# Generated by OpenFakeRAM
VERSION 5.7 ;
BUSBITCHARS "[]" ;
PROPERTYDEFINITIONS
  MACRO width INTEGER ;
  MACRO depth INTEGER ;
  MACRO banks INTEGER ;
END PROPERTYDEFINITIONS
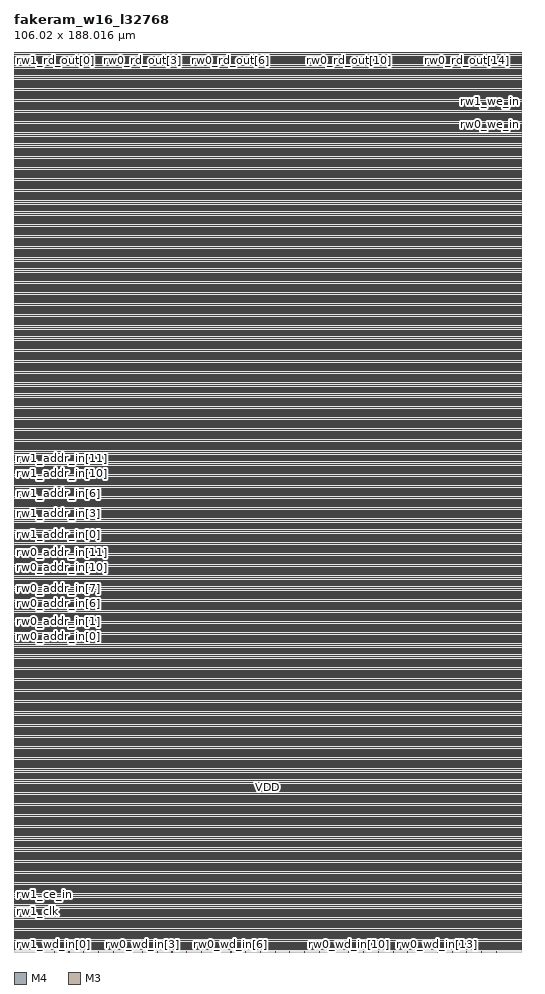
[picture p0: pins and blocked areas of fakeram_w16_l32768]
MACRO fakeram_w16_l32768
  PROPERTY width 16 ;
  PROPERTY depth 16384 ;
  PROPERTY banks 1 ;
  FOREIGN fakeram_w16_l32768 0 0 ;
  SYMMETRY X Y R90 ;
  SIZE 106.020 BY 188.016 ;
  CLASS BLOCK ;
  PIN rw0_clk
    DIRECTION INPUT ;
    USE SIGNAL ;
    SHAPE ABUTMENT ;
    PORT
      LAYER M4 ;
      RECT 0.000 5.652 0.048 5.676 ;
    END
  END rw0_clk
  PIN rw0_ce_in
    DIRECTION INPUT ;
    USE SIGNAL ;
    SHAPE ABUTMENT ;
    PORT
      LAYER M4 ;
      RECT 0.000 7.476 0.048 7.500 ;
    END
  END rw0_ce_in
  PIN rw1_clk
    DIRECTION INPUT ;
    USE SIGNAL ;
    SHAPE ABUTMENT ;
    PORT
      LAYER M4 ;
      RECT 0.000 8.484 0.048 8.508 ;
    END
  END rw1_clk
  PIN rw1_ce_in
    DIRECTION INPUT ;
    USE SIGNAL ;
    SHAPE ABUTMENT ;
    PORT
      LAYER M4 ;
      RECT 0.000 10.308 0.048 10.332 ;
    END
  END rw1_ce_in
  PIN rw0_addr_in[0]
    DIRECTION INPUT ;
    USE SIGNAL ;
    SHAPE ABUTMENT ;
    PORT
      LAYER M4 ;
      RECT 0.000 65.844 0.048 65.868 ;
    END
  END rw0_addr_in[0]
  PIN rw0_addr_in[1]
    DIRECTION INPUT ;
    USE SIGNAL ;
    SHAPE ABUTMENT ;
    PORT
      LAYER M4 ;
      RECT 0.000 67.284 0.048 67.308 ;
    END
  END rw0_addr_in[1]
  PIN rw0_addr_in[2]
    DIRECTION INPUT ;
    USE SIGNAL ;
    SHAPE ABUTMENT ;
    PORT
      LAYER M4 ;
      RECT 0.000 68.724 0.048 68.748 ;
    END
  END rw0_addr_in[2]
  PIN rw0_addr_in[3]
    DIRECTION INPUT ;
    USE SIGNAL ;
    SHAPE ABUTMENT ;
    PORT
      LAYER M4 ;
      RECT 0.000 70.164 0.048 70.188 ;
    END
  END rw0_addr_in[3]
  PIN rw0_addr_in[4]
    DIRECTION INPUT ;
    USE SIGNAL ;
    SHAPE ABUTMENT ;
    PORT
      LAYER M4 ;
      RECT 0.000 71.604 0.048 71.628 ;
    END
  END rw0_addr_in[4]
  PIN rw0_addr_in[5]
    DIRECTION INPUT ;
    USE SIGNAL ;
    SHAPE ABUTMENT ;
    PORT
      LAYER M4 ;
      RECT 0.000 73.044 0.048 73.068 ;
    END
  END rw0_addr_in[5]
  PIN rw0_addr_in[6]
    DIRECTION INPUT ;
    USE SIGNAL ;
    SHAPE ABUTMENT ;
    PORT
      LAYER M4 ;
      RECT 0.000 74.484 0.048 74.508 ;
    END
  END rw0_addr_in[6]
  PIN rw0_addr_in[7]
    DIRECTION INPUT ;
    USE SIGNAL ;
    SHAPE ABUTMENT ;
    PORT
      LAYER M4 ;
      RECT 0.000 75.924 0.048 75.948 ;
    END
  END rw0_addr_in[7]
  PIN rw0_addr_in[8]
    DIRECTION INPUT ;
    USE SIGNAL ;
    SHAPE ABUTMENT ;
    PORT
      LAYER M4 ;
      RECT 0.000 77.364 0.048 77.388 ;
    END
  END rw0_addr_in[8]
  PIN rw0_addr_in[9]
    DIRECTION INPUT ;
    USE SIGNAL ;
    SHAPE ABUTMENT ;
    PORT
      LAYER M4 ;
      RECT 0.000 78.804 0.048 78.828 ;
    END
  END rw0_addr_in[9]
  PIN rw0_addr_in[10]
    DIRECTION INPUT ;
    USE SIGNAL ;
    SHAPE ABUTMENT ;
    PORT
      LAYER M4 ;
      RECT 0.000 80.244 0.048 80.268 ;
    END
  END rw0_addr_in[10]
  PIN rw0_addr_in[11]
    DIRECTION INPUT ;
    USE SIGNAL ;
    SHAPE ABUTMENT ;
    PORT
      LAYER M4 ;
      RECT 0.000 81.684 0.048 81.708 ;
    END
  END rw0_addr_in[11]
  PIN rw0_addr_in[12]
    DIRECTION INPUT ;
    USE SIGNAL ;
    SHAPE ABUTMENT ;
    PORT
      LAYER M4 ;
      RECT 0.000 83.124 0.048 83.148 ;
    END
  END rw0_addr_in[12]
  PIN rw0_addr_in[13]
    DIRECTION INPUT ;
    USE SIGNAL ;
    SHAPE ABUTMENT ;
    PORT
      LAYER M4 ;
      RECT 0.000 84.564 0.048 84.588 ;
    END
  END rw0_addr_in[13]
  PIN rw1_addr_in[0]
    DIRECTION INPUT ;
    USE SIGNAL ;
    SHAPE ABUTMENT ;
    PORT
      LAYER M4 ;
      RECT 0.000 85.572 0.048 85.596 ;
    END
  END rw1_addr_in[0]
  PIN rw1_addr_in[1]
    DIRECTION INPUT ;
    USE SIGNAL ;
    SHAPE ABUTMENT ;
    PORT
      LAYER M4 ;
      RECT 0.000 87.012 0.048 87.036 ;
    END
  END rw1_addr_in[1]
  PIN rw1_addr_in[2]
    DIRECTION INPUT ;
    USE SIGNAL ;
    SHAPE ABUTMENT ;
    PORT
      LAYER M4 ;
      RECT 0.000 88.452 0.048 88.476 ;
    END
  END rw1_addr_in[2]
  PIN rw1_addr_in[3]
    DIRECTION INPUT ;
    USE SIGNAL ;
    SHAPE ABUTMENT ;
    PORT
      LAYER M4 ;
      RECT 0.000 89.892 0.048 89.916 ;
    END
  END rw1_addr_in[3]
  PIN rw1_addr_in[4]
    DIRECTION INPUT ;
    USE SIGNAL ;
    SHAPE ABUTMENT ;
    PORT
      LAYER M4 ;
      RECT 0.000 91.332 0.048 91.356 ;
    END
  END rw1_addr_in[4]
  PIN rw1_addr_in[5]
    DIRECTION INPUT ;
    USE SIGNAL ;
    SHAPE ABUTMENT ;
    PORT
      LAYER M4 ;
      RECT 0.000 92.772 0.048 92.796 ;
    END
  END rw1_addr_in[5]
  PIN rw1_addr_in[6]
    DIRECTION INPUT ;
    USE SIGNAL ;
    SHAPE ABUTMENT ;
    PORT
      LAYER M4 ;
      RECT 0.000 94.212 0.048 94.236 ;
    END
  END rw1_addr_in[6]
  PIN rw1_addr_in[7]
    DIRECTION INPUT ;
    USE SIGNAL ;
    SHAPE ABUTMENT ;
    PORT
      LAYER M4 ;
      RECT 0.000 95.700 0.048 95.724 ;
    END
  END rw1_addr_in[7]
  PIN rw1_addr_in[8]
    DIRECTION INPUT ;
    USE SIGNAL ;
    SHAPE ABUTMENT ;
    PORT
      LAYER M4 ;
      RECT 0.000 97.140 0.048 97.164 ;
    END
  END rw1_addr_in[8]
  PIN rw1_addr_in[9]
    DIRECTION INPUT ;
    USE SIGNAL ;
    SHAPE ABUTMENT ;
    PORT
      LAYER M4 ;
      RECT 0.000 98.580 0.048 98.604 ;
    END
  END rw1_addr_in[9]
  PIN rw1_addr_in[10]
    DIRECTION INPUT ;
    USE SIGNAL ;
    SHAPE ABUTMENT ;
    PORT
      LAYER M4 ;
      RECT 0.000 100.020 0.048 100.044 ;
    END
  END rw1_addr_in[10]
  PIN rw1_addr_in[11]
    DIRECTION INPUT ;
    USE SIGNAL ;
    SHAPE ABUTMENT ;
    PORT
      LAYER M4 ;
      RECT 0.000 101.460 0.048 101.484 ;
    END
  END rw1_addr_in[11]
  PIN rw1_addr_in[12]
    DIRECTION INPUT ;
    USE SIGNAL ;
    SHAPE ABUTMENT ;
    PORT
      LAYER M4 ;
      RECT 0.000 102.900 0.048 102.924 ;
    END
  END rw1_addr_in[12]
  PIN rw1_addr_in[13]
    DIRECTION INPUT ;
    USE SIGNAL ;
    SHAPE ABUTMENT ;
    PORT
      LAYER M4 ;
      RECT 0.000 104.340 0.048 104.364 ;
    END
  END rw1_addr_in[13]
  PIN rw1_rd_out[0]
    DIRECTION OUTPUT ;
    USE SIGNAL ;
    SHAPE ABUTMENT ;
    PORT
      LAYER M3 ;
      RECT 5.319 187.980 5.337 188.016 ;
    END
  END rw1_rd_out[0]
  PIN rw0_rd_out[0]
    DIRECTION OUTPUT ;
    USE SIGNAL ;
    SHAPE ABUTMENT ;
    PORT
      LAYER M3 ;
      RECT 8.379 187.980 8.397 188.016 ;
    END
  END rw0_rd_out[0]
  PIN rw1_rd_out[1]
    DIRECTION OUTPUT ;
    USE SIGNAL ;
    SHAPE ABUTMENT ;
    PORT
      LAYER M3 ;
      RECT 11.475 187.980 11.493 188.016 ;
    END
  END rw1_rd_out[1]
  PIN rw0_rd_out[1]
    DIRECTION OUTPUT ;
    USE SIGNAL ;
    SHAPE ABUTMENT ;
    PORT
      LAYER M3 ;
      RECT 14.535 187.980 14.553 188.016 ;
    END
  END rw0_rd_out[1]
  PIN rw1_rd_out[2]
    DIRECTION OUTPUT ;
    USE SIGNAL ;
    SHAPE ABUTMENT ;
    PORT
      LAYER M3 ;
      RECT 17.631 187.980 17.649 188.016 ;
    END
  END rw1_rd_out[2]
  PIN rw0_rd_out[2]
    DIRECTION OUTPUT ;
    USE SIGNAL ;
    SHAPE ABUTMENT ;
    PORT
      LAYER M3 ;
      RECT 20.691 187.980 20.709 188.016 ;
    END
  END rw0_rd_out[2]
  PIN rw1_rd_out[3]
    DIRECTION OUTPUT ;
    USE SIGNAL ;
    SHAPE ABUTMENT ;
    PORT
      LAYER M3 ;
      RECT 23.787 187.980 23.805 188.016 ;
    END
  END rw1_rd_out[3]
  PIN rw0_rd_out[3]
    DIRECTION OUTPUT ;
    USE SIGNAL ;
    SHAPE ABUTMENT ;
    PORT
      LAYER M3 ;
      RECT 26.847 187.980 26.865 188.016 ;
    END
  END rw0_rd_out[3]
  PIN rw1_rd_out[4]
    DIRECTION OUTPUT ;
    USE SIGNAL ;
    SHAPE ABUTMENT ;
    PORT
      LAYER M3 ;
      RECT 29.943 187.980 29.961 188.016 ;
    END
  END rw1_rd_out[4]
  PIN rw0_rd_out[4]
    DIRECTION OUTPUT ;
    USE SIGNAL ;
    SHAPE ABUTMENT ;
    PORT
      LAYER M3 ;
      RECT 33.003 187.980 33.021 188.016 ;
    END
  END rw0_rd_out[4]
  PIN rw1_rd_out[5]
    DIRECTION OUTPUT ;
    USE SIGNAL ;
    SHAPE ABUTMENT ;
    PORT
      LAYER M3 ;
      RECT 36.099 187.980 36.117 188.016 ;
    END
  END rw1_rd_out[5]
  PIN rw0_rd_out[5]
    DIRECTION OUTPUT ;
    USE SIGNAL ;
    SHAPE ABUTMENT ;
    PORT
      LAYER M3 ;
      RECT 39.159 187.980 39.177 188.016 ;
    END
  END rw0_rd_out[5]
  PIN rw1_rd_out[6]
    DIRECTION OUTPUT ;
    USE SIGNAL ;
    SHAPE ABUTMENT ;
    PORT
      LAYER M3 ;
      RECT 42.255 187.980 42.273 188.016 ;
    END
  END rw1_rd_out[6]
  PIN rw0_rd_out[6]
    DIRECTION OUTPUT ;
    USE SIGNAL ;
    SHAPE ABUTMENT ;
    PORT
      LAYER M3 ;
      RECT 45.315 187.980 45.333 188.016 ;
    END
  END rw0_rd_out[6]
  PIN rw1_rd_out[7]
    DIRECTION OUTPUT ;
    USE SIGNAL ;
    SHAPE ABUTMENT ;
    PORT
      LAYER M3 ;
      RECT 48.411 187.980 48.429 188.016 ;
    END
  END rw1_rd_out[7]
  PIN rw0_rd_out[7]
    DIRECTION OUTPUT ;
    USE SIGNAL ;
    SHAPE ABUTMENT ;
    PORT
      LAYER M3 ;
      RECT 51.471 187.980 51.489 188.016 ;
    END
  END rw0_rd_out[7]
  PIN rw1_rd_out[8]
    DIRECTION OUTPUT ;
    USE SIGNAL ;
    SHAPE ABUTMENT ;
    PORT
      LAYER M3 ;
      RECT 54.567 187.980 54.585 188.016 ;
    END
  END rw1_rd_out[8]
  PIN rw0_rd_out[8]
    DIRECTION OUTPUT ;
    USE SIGNAL ;
    SHAPE ABUTMENT ;
    PORT
      LAYER M3 ;
      RECT 57.627 187.980 57.645 188.016 ;
    END
  END rw0_rd_out[8]
  PIN rw1_rd_out[9]
    DIRECTION OUTPUT ;
    USE SIGNAL ;
    SHAPE ABUTMENT ;
    PORT
      LAYER M3 ;
      RECT 60.723 187.980 60.741 188.016 ;
    END
  END rw1_rd_out[9]
  PIN rw0_rd_out[9]
    DIRECTION OUTPUT ;
    USE SIGNAL ;
    SHAPE ABUTMENT ;
    PORT
      LAYER M3 ;
      RECT 63.783 187.980 63.801 188.016 ;
    END
  END rw0_rd_out[9]
  PIN rw1_rd_out[10]
    DIRECTION OUTPUT ;
    USE SIGNAL ;
    SHAPE ABUTMENT ;
    PORT
      LAYER M3 ;
      RECT 66.879 187.980 66.897 188.016 ;
    END
  END rw1_rd_out[10]
  PIN rw0_rd_out[10]
    DIRECTION OUTPUT ;
    USE SIGNAL ;
    SHAPE ABUTMENT ;
    PORT
      LAYER M3 ;
      RECT 69.939 187.980 69.957 188.016 ;
    END
  END rw0_rd_out[10]
  PIN rw1_rd_out[11]
    DIRECTION OUTPUT ;
    USE SIGNAL ;
    SHAPE ABUTMENT ;
    PORT
      LAYER M3 ;
      RECT 73.035 187.980 73.053 188.016 ;
    END
  END rw1_rd_out[11]
  PIN rw0_rd_out[11]
    DIRECTION OUTPUT ;
    USE SIGNAL ;
    SHAPE ABUTMENT ;
    PORT
      LAYER M3 ;
      RECT 76.095 187.980 76.113 188.016 ;
    END
  END rw0_rd_out[11]
  PIN rw1_rd_out[12]
    DIRECTION OUTPUT ;
    USE SIGNAL ;
    SHAPE ABUTMENT ;
    PORT
      LAYER M3 ;
      RECT 79.191 187.980 79.209 188.016 ;
    END
  END rw1_rd_out[12]
  PIN rw0_rd_out[12]
    DIRECTION OUTPUT ;
    USE SIGNAL ;
    SHAPE ABUTMENT ;
    PORT
      LAYER M3 ;
      RECT 82.251 187.980 82.269 188.016 ;
    END
  END rw0_rd_out[12]
  PIN rw1_rd_out[13]
    DIRECTION OUTPUT ;
    USE SIGNAL ;
    SHAPE ABUTMENT ;
    PORT
      LAYER M3 ;
      RECT 85.347 187.980 85.365 188.016 ;
    END
  END rw1_rd_out[13]
  PIN rw0_rd_out[13]
    DIRECTION OUTPUT ;
    USE SIGNAL ;
    SHAPE ABUTMENT ;
    PORT
      LAYER M3 ;
      RECT 88.407 187.980 88.425 188.016 ;
    END
  END rw0_rd_out[13]
  PIN rw1_rd_out[14]
    DIRECTION OUTPUT ;
    USE SIGNAL ;
    SHAPE ABUTMENT ;
    PORT
      LAYER M3 ;
      RECT 91.503 187.980 91.521 188.016 ;
    END
  END rw1_rd_out[14]
  PIN rw0_rd_out[14]
    DIRECTION OUTPUT ;
    USE SIGNAL ;
    SHAPE ABUTMENT ;
    PORT
      LAYER M3 ;
      RECT 94.563 187.980 94.581 188.016 ;
    END
  END rw0_rd_out[14]
  PIN rw1_rd_out[15]
    DIRECTION OUTPUT ;
    USE SIGNAL ;
    SHAPE ABUTMENT ;
    PORT
      LAYER M3 ;
      RECT 97.659 187.980 97.677 188.016 ;
    END
  END rw1_rd_out[15]
  PIN rw0_rd_out[15]
    DIRECTION OUTPUT ;
    USE SIGNAL ;
    SHAPE ABUTMENT ;
    PORT
      LAYER M3 ;
      RECT 100.719 187.980 100.737 188.016 ;
    END
  END rw0_rd_out[15]
  PIN rw0_we_in
    DIRECTION INPUT ;
    USE SIGNAL ;
    SHAPE ABUTMENT ;
    PORT
      LAYER M4 ;
      RECT 105.972 172.932 106.020 172.956 ;
    END
  END rw0_we_in
  PIN rw1_we_in
    DIRECTION INPUT ;
    USE SIGNAL ;
    SHAPE ABUTMENT ;
    PORT
      LAYER M4 ;
      RECT 105.972 177.636 106.020 177.660 ;
    END
  END rw1_we_in
  PIN rw1_wd_in[0]
    DIRECTION INPUT ;
    USE SIGNAL ;
    SHAPE ABUTMENT ;
    PORT
      LAYER M3 ;
      RECT 5.319 0.000 5.337 0.036 ;
    END
  END rw1_wd_in[0]
  PIN rw0_wd_in[0]
    DIRECTION INPUT ;
    USE SIGNAL ;
    SHAPE ABUTMENT ;
    PORT
      LAYER M3 ;
      RECT 8.379 0.000 8.397 0.036 ;
    END
  END rw0_wd_in[0]
  PIN rw1_wd_in[1]
    DIRECTION INPUT ;
    USE SIGNAL ;
    SHAPE ABUTMENT ;
    PORT
      LAYER M3 ;
      RECT 11.475 0.000 11.493 0.036 ;
    END
  END rw1_wd_in[1]
  PIN rw0_wd_in[1]
    DIRECTION INPUT ;
    USE SIGNAL ;
    SHAPE ABUTMENT ;
    PORT
      LAYER M3 ;
      RECT 14.535 0.000 14.553 0.036 ;
    END
  END rw0_wd_in[1]
  PIN rw1_wd_in[2]
    DIRECTION INPUT ;
    USE SIGNAL ;
    SHAPE ABUTMENT ;
    PORT
      LAYER M3 ;
      RECT 17.631 0.000 17.649 0.036 ;
    END
  END rw1_wd_in[2]
  PIN rw0_wd_in[2]
    DIRECTION INPUT ;
    USE SIGNAL ;
    SHAPE ABUTMENT ;
    PORT
      LAYER M3 ;
      RECT 20.691 0.000 20.709 0.036 ;
    END
  END rw0_wd_in[2]
  PIN rw1_wd_in[3]
    DIRECTION INPUT ;
    USE SIGNAL ;
    SHAPE ABUTMENT ;
    PORT
      LAYER M3 ;
      RECT 23.787 0.000 23.805 0.036 ;
    END
  END rw1_wd_in[3]
  PIN rw0_wd_in[3]
    DIRECTION INPUT ;
    USE SIGNAL ;
    SHAPE ABUTMENT ;
    PORT
      LAYER M3 ;
      RECT 26.847 0.000 26.865 0.036 ;
    END
  END rw0_wd_in[3]
  PIN rw1_wd_in[4]
    DIRECTION INPUT ;
    USE SIGNAL ;
    SHAPE ABUTMENT ;
    PORT
      LAYER M3 ;
      RECT 29.943 0.000 29.961 0.036 ;
    END
  END rw1_wd_in[4]
  PIN rw0_wd_in[4]
    DIRECTION INPUT ;
    USE SIGNAL ;
    SHAPE ABUTMENT ;
    PORT
      LAYER M3 ;
      RECT 33.003 0.000 33.021 0.036 ;
    END
  END rw0_wd_in[4]
  PIN rw1_wd_in[5]
    DIRECTION INPUT ;
    USE SIGNAL ;
    SHAPE ABUTMENT ;
    PORT
      LAYER M3 ;
      RECT 36.099 0.000 36.117 0.036 ;
    END
  END rw1_wd_in[5]
  PIN rw0_wd_in[5]
    DIRECTION INPUT ;
    USE SIGNAL ;
    SHAPE ABUTMENT ;
    PORT
      LAYER M3 ;
      RECT 39.159 0.000 39.177 0.036 ;
    END
  END rw0_wd_in[5]
  PIN rw1_wd_in[6]
    DIRECTION INPUT ;
    USE SIGNAL ;
    SHAPE ABUTMENT ;
    PORT
      LAYER M3 ;
      RECT 42.255 0.000 42.273 0.036 ;
    END
  END rw1_wd_in[6]
  PIN rw0_wd_in[6]
    DIRECTION INPUT ;
    USE SIGNAL ;
    SHAPE ABUTMENT ;
    PORT
      LAYER M3 ;
      RECT 45.315 0.000 45.333 0.036 ;
    END
  END rw0_wd_in[6]
  PIN rw1_wd_in[7]
    DIRECTION INPUT ;
    USE SIGNAL ;
    SHAPE ABUTMENT ;
    PORT
      LAYER M3 ;
      RECT 48.411 0.000 48.429 0.036 ;
    END
  END rw1_wd_in[7]
  PIN rw0_wd_in[7]
    DIRECTION INPUT ;
    USE SIGNAL ;
    SHAPE ABUTMENT ;
    PORT
      LAYER M3 ;
      RECT 51.471 0.000 51.489 0.036 ;
    END
  END rw0_wd_in[7]
  PIN rw1_wd_in[8]
    DIRECTION INPUT ;
    USE SIGNAL ;
    SHAPE ABUTMENT ;
    PORT
      LAYER M3 ;
      RECT 54.567 0.000 54.585 0.036 ;
    END
  END rw1_wd_in[8]
  PIN rw0_wd_in[8]
    DIRECTION INPUT ;
    USE SIGNAL ;
    SHAPE ABUTMENT ;
    PORT
      LAYER M3 ;
      RECT 57.627 0.000 57.645 0.036 ;
    END
  END rw0_wd_in[8]
  PIN rw1_wd_in[9]
    DIRECTION INPUT ;
    USE SIGNAL ;
    SHAPE ABUTMENT ;
    PORT
      LAYER M3 ;
      RECT 60.723 0.000 60.741 0.036 ;
    END
  END rw1_wd_in[9]
  PIN rw0_wd_in[9]
    DIRECTION INPUT ;
    USE SIGNAL ;
    SHAPE ABUTMENT ;
    PORT
      LAYER M3 ;
      RECT 63.783 0.000 63.801 0.036 ;
    END
  END rw0_wd_in[9]
  PIN rw1_wd_in[10]
    DIRECTION INPUT ;
    USE SIGNAL ;
    SHAPE ABUTMENT ;
    PORT
      LAYER M3 ;
      RECT 66.879 0.000 66.897 0.036 ;
    END
  END rw1_wd_in[10]
  PIN rw0_wd_in[10]
    DIRECTION INPUT ;
    USE SIGNAL ;
    SHAPE ABUTMENT ;
    PORT
      LAYER M3 ;
      RECT 69.939 0.000 69.957 0.036 ;
    END
  END rw0_wd_in[10]
  PIN rw1_wd_in[11]
    DIRECTION INPUT ;
    USE SIGNAL ;
    SHAPE ABUTMENT ;
    PORT
      LAYER M3 ;
      RECT 73.035 0.000 73.053 0.036 ;
    END
  END rw1_wd_in[11]
  PIN rw0_wd_in[11]
    DIRECTION INPUT ;
    USE SIGNAL ;
    SHAPE ABUTMENT ;
    PORT
      LAYER M3 ;
      RECT 76.095 0.000 76.113 0.036 ;
    END
  END rw0_wd_in[11]
  PIN rw1_wd_in[12]
    DIRECTION INPUT ;
    USE SIGNAL ;
    SHAPE ABUTMENT ;
    PORT
      LAYER M3 ;
      RECT 79.191 0.000 79.209 0.036 ;
    END
  END rw1_wd_in[12]
  PIN rw0_wd_in[12]
    DIRECTION INPUT ;
    USE SIGNAL ;
    SHAPE ABUTMENT ;
    PORT
      LAYER M3 ;
      RECT 82.251 0.000 82.269 0.036 ;
    END
  END rw0_wd_in[12]
  PIN rw1_wd_in[13]
    DIRECTION INPUT ;
    USE SIGNAL ;
    SHAPE ABUTMENT ;
    PORT
      LAYER M3 ;
      RECT 85.347 0.000 85.365 0.036 ;
    END
  END rw1_wd_in[13]
  PIN rw0_wd_in[13]
    DIRECTION INPUT ;
    USE SIGNAL ;
    SHAPE ABUTMENT ;
    PORT
      LAYER M3 ;
      RECT 88.407 0.000 88.425 0.036 ;
    END
  END rw0_wd_in[13]
  PIN rw1_wd_in[14]
    DIRECTION INPUT ;
    USE SIGNAL ;
    SHAPE ABUTMENT ;
    PORT
      LAYER M3 ;
      RECT 91.503 0.000 91.521 0.036 ;
    END
  END rw1_wd_in[14]
  PIN rw0_wd_in[14]
    DIRECTION INPUT ;
    USE SIGNAL ;
    SHAPE ABUTMENT ;
    PORT
      LAYER M3 ;
      RECT 94.563 0.000 94.581 0.036 ;
    END
  END rw0_wd_in[14]
  PIN rw1_wd_in[15]
    DIRECTION INPUT ;
    USE SIGNAL ;
    SHAPE ABUTMENT ;
    PORT
      LAYER M3 ;
      RECT 97.659 0.000 97.677 0.036 ;
    END
  END rw1_wd_in[15]
  PIN rw0_wd_in[15]
    DIRECTION INPUT ;
    USE SIGNAL ;
    SHAPE ABUTMENT ;
    PORT
      LAYER M3 ;
      RECT 100.719 0.000 100.737 0.036 ;
    END
  END rw0_wd_in[15]
  PIN VSS
    DIRECTION INOUT ;
    USE GROUND ;
    PORT
      LAYER M4 ;
      RECT 0.096 0.816 105.924 0.912 ;
      RECT 0.096 1.584 105.924 1.680 ;
      RECT 0.096 2.352 105.924 2.448 ;
      RECT 0.096 3.120 105.924 3.216 ;
      RECT 0.096 3.888 105.924 3.984 ;
      RECT 0.096 4.656 105.924 4.752 ;
      RECT 0.096 5.424 105.924 5.520 ;
      RECT 0.096 6.192 105.924 6.288 ;
      RECT 0.096 6.960 105.924 7.056 ;
      RECT 0.096 7.728 105.924 7.824 ;
      RECT 0.096 8.496 105.924 8.592 ;
      RECT 0.096 9.264 105.924 9.360 ;
      RECT 0.096 10.032 105.924 10.128 ;
      RECT 0.096 10.800 105.924 10.896 ;
      RECT 0.096 11.568 105.924 11.664 ;
      RECT 0.096 12.336 105.924 12.432 ;
      RECT 0.096 13.104 105.924 13.200 ;
      RECT 0.096 13.872 105.924 13.968 ;
      RECT 0.096 14.640 105.924 14.736 ;
      RECT 0.096 15.408 105.924 15.504 ;
      RECT 0.096 16.176 105.924 16.272 ;
      RECT 0.096 16.944 105.924 17.040 ;
      RECT 0.096 17.712 105.924 17.808 ;
      RECT 0.096 18.480 105.924 18.576 ;
      RECT 0.096 19.248 105.924 19.344 ;
      RECT 0.096 20.016 105.924 20.112 ;
      RECT 0.096 20.784 105.924 20.880 ;
      RECT 0.096 21.552 105.924 21.648 ;
      RECT 0.096 22.320 105.924 22.416 ;
      RECT 0.096 23.088 105.924 23.184 ;
      RECT 0.096 23.856 105.924 23.952 ;
      RECT 0.096 24.624 105.924 24.720 ;
      RECT 0.096 25.392 105.924 25.488 ;
      RECT 0.096 26.160 105.924 26.256 ;
      RECT 0.096 26.928 105.924 27.024 ;
      RECT 0.096 27.696 105.924 27.792 ;
      RECT 0.096 28.464 105.924 28.560 ;
      RECT 0.096 29.232 105.924 29.328 ;
      RECT 0.096 30.000 105.924 30.096 ;
      RECT 0.096 30.768 105.924 30.864 ;
      RECT 0.096 31.536 105.924 31.632 ;
      RECT 0.096 32.304 105.924 32.400 ;
      RECT 0.096 33.072 105.924 33.168 ;
      RECT 0.096 33.840 105.924 33.936 ;
      RECT 0.096 34.608 105.924 34.704 ;
      RECT 0.096 35.376 105.924 35.472 ;
      RECT 0.096 36.144 105.924 36.240 ;
      RECT 0.096 36.912 105.924 37.008 ;
      RECT 0.096 37.680 105.924 37.776 ;
      RECT 0.096 38.448 105.924 38.544 ;
      RECT 0.096 39.216 105.924 39.312 ;
      RECT 0.096 39.984 105.924 40.080 ;
      RECT 0.096 40.752 105.924 40.848 ;
      RECT 0.096 41.520 105.924 41.616 ;
      RECT 0.096 42.288 105.924 42.384 ;
      RECT 0.096 43.056 105.924 43.152 ;
      RECT 0.096 43.824 105.924 43.920 ;
      RECT 0.096 44.592 105.924 44.688 ;
      RECT 0.096 45.360 105.924 45.456 ;
      RECT 0.096 46.128 105.924 46.224 ;
      RECT 0.096 46.896 105.924 46.992 ;
      RECT 0.096 47.664 105.924 47.760 ;
      RECT 0.096 48.432 105.924 48.528 ;
      RECT 0.096 49.200 105.924 49.296 ;
      RECT 0.096 49.968 105.924 50.064 ;
      RECT 0.096 50.736 105.924 50.832 ;
      RECT 0.096 51.504 105.924 51.600 ;
      RECT 0.096 52.272 105.924 52.368 ;
      RECT 0.096 53.040 105.924 53.136 ;
      RECT 0.096 53.808 105.924 53.904 ;
      RECT 0.096 54.576 105.924 54.672 ;
      RECT 0.096 55.344 105.924 55.440 ;
      RECT 0.096 56.112 105.924 56.208 ;
      RECT 0.096 56.880 105.924 56.976 ;
      RECT 0.096 57.648 105.924 57.744 ;
      RECT 0.096 58.416 105.924 58.512 ;
      RECT 0.096 59.184 105.924 59.280 ;
      RECT 0.096 59.952 105.924 60.048 ;
      RECT 0.096 60.720 105.924 60.816 ;
      RECT 0.096 61.488 105.924 61.584 ;
      RECT 0.096 62.256 105.924 62.352 ;
      RECT 0.096 63.024 105.924 63.120 ;
      RECT 0.096 63.792 105.924 63.888 ;
      RECT 0.096 64.560 105.924 64.656 ;
      RECT 0.096 65.328 105.924 65.424 ;
      RECT 0.096 66.096 105.924 66.192 ;
      RECT 0.096 66.864 105.924 66.960 ;
      RECT 0.096 67.632 105.924 67.728 ;
      RECT 0.096 68.400 105.924 68.496 ;
      RECT 0.096 69.168 105.924 69.264 ;
      RECT 0.096 69.936 105.924 70.032 ;
      RECT 0.096 70.704 105.924 70.800 ;
      RECT 0.096 71.472 105.924 71.568 ;
      RECT 0.096 72.240 105.924 72.336 ;
      RECT 0.096 73.008 105.924 73.104 ;
      RECT 0.096 73.776 105.924 73.872 ;
      RECT 0.096 74.544 105.924 74.640 ;
      RECT 0.096 75.312 105.924 75.408 ;
      RECT 0.096 76.080 105.924 76.176 ;
      RECT 0.096 76.848 105.924 76.944 ;
      RECT 0.096 77.616 105.924 77.712 ;
      RECT 0.096 78.384 105.924 78.480 ;
      RECT 0.096 79.152 105.924 79.248 ;
      RECT 0.096 79.920 105.924 80.016 ;
      RECT 0.096 80.688 105.924 80.784 ;
      RECT 0.096 81.456 105.924 81.552 ;
      RECT 0.096 82.224 105.924 82.320 ;
      RECT 0.096 82.992 105.924 83.088 ;
      RECT 0.096 83.760 105.924 83.856 ;
      RECT 0.096 84.528 105.924 84.624 ;
      RECT 0.096 85.296 105.924 85.392 ;
      RECT 0.096 86.064 105.924 86.160 ;
      RECT 0.096 86.832 105.924 86.928 ;
      RECT 0.096 87.600 105.924 87.696 ;
      RECT 0.096 88.368 105.924 88.464 ;
      RECT 0.096 89.136 105.924 89.232 ;
      RECT 0.096 89.904 105.924 90.000 ;
      RECT 0.096 90.672 105.924 90.768 ;
      RECT 0.096 91.440 105.924 91.536 ;
      RECT 0.096 92.208 105.924 92.304 ;
      RECT 0.096 92.976 105.924 93.072 ;
      RECT 0.096 93.744 105.924 93.840 ;
      RECT 0.096 94.512 105.924 94.608 ;
      RECT 0.096 95.280 105.924 95.376 ;
      RECT 0.096 96.048 105.924 96.144 ;
      RECT 0.096 96.816 105.924 96.912 ;
      RECT 0.096 97.584 105.924 97.680 ;
      RECT 0.096 98.352 105.924 98.448 ;
      RECT 0.096 99.120 105.924 99.216 ;
      RECT 0.096 99.888 105.924 99.984 ;
      RECT 0.096 100.656 105.924 100.752 ;
      RECT 0.096 101.424 105.924 101.520 ;
      RECT 0.096 102.192 105.924 102.288 ;
      RECT 0.096 102.960 105.924 103.056 ;
      RECT 0.096 103.728 105.924 103.824 ;
      RECT 0.096 104.496 105.924 104.592 ;
      RECT 0.096 105.264 105.924 105.360 ;
      RECT 0.096 106.032 105.924 106.128 ;
      RECT 0.096 106.800 105.924 106.896 ;
      RECT 0.096 107.568 105.924 107.664 ;
      RECT 0.096 108.336 105.924 108.432 ;
      RECT 0.096 109.104 105.924 109.200 ;
      RECT 0.096 109.872 105.924 109.968 ;
      RECT 0.096 110.640 105.924 110.736 ;
      RECT 0.096 111.408 105.924 111.504 ;
      RECT 0.096 112.176 105.924 112.272 ;
      RECT 0.096 112.944 105.924 113.040 ;
      RECT 0.096 113.712 105.924 113.808 ;
      RECT 0.096 114.480 105.924 114.576 ;
      RECT 0.096 115.248 105.924 115.344 ;
      RECT 0.096 116.016 105.924 116.112 ;
      RECT 0.096 116.784 105.924 116.880 ;
      RECT 0.096 117.552 105.924 117.648 ;
      RECT 0.096 118.320 105.924 118.416 ;
      RECT 0.096 119.088 105.924 119.184 ;
      RECT 0.096 119.856 105.924 119.952 ;
      RECT 0.096 120.624 105.924 120.720 ;
      RECT 0.096 121.392 105.924 121.488 ;
      RECT 0.096 122.160 105.924 122.256 ;
      RECT 0.096 122.928 105.924 123.024 ;
      RECT 0.096 123.696 105.924 123.792 ;
      RECT 0.096 124.464 105.924 124.560 ;
      RECT 0.096 125.232 105.924 125.328 ;
      RECT 0.096 126.000 105.924 126.096 ;
      RECT 0.096 126.768 105.924 126.864 ;
      RECT 0.096 127.536 105.924 127.632 ;
      RECT 0.096 128.304 105.924 128.400 ;
      RECT 0.096 129.072 105.924 129.168 ;
      RECT 0.096 129.840 105.924 129.936 ;
      RECT 0.096 130.608 105.924 130.704 ;
      RECT 0.096 131.376 105.924 131.472 ;
      RECT 0.096 132.144 105.924 132.240 ;
      RECT 0.096 132.912 105.924 133.008 ;
      RECT 0.096 133.680 105.924 133.776 ;
      RECT 0.096 134.448 105.924 134.544 ;
      RECT 0.096 135.216 105.924 135.312 ;
      RECT 0.096 135.984 105.924 136.080 ;
      RECT 0.096 136.752 105.924 136.848 ;
      RECT 0.096 137.520 105.924 137.616 ;
      RECT 0.096 138.288 105.924 138.384 ;
      RECT 0.096 139.056 105.924 139.152 ;
      RECT 0.096 139.824 105.924 139.920 ;
      RECT 0.096 140.592 105.924 140.688 ;
      RECT 0.096 141.360 105.924 141.456 ;
      RECT 0.096 142.128 105.924 142.224 ;
      RECT 0.096 142.896 105.924 142.992 ;
      RECT 0.096 143.664 105.924 143.760 ;
      RECT 0.096 144.432 105.924 144.528 ;
      RECT 0.096 145.200 105.924 145.296 ;
      RECT 0.096 145.968 105.924 146.064 ;
      RECT 0.096 146.736 105.924 146.832 ;
      RECT 0.096 147.504 105.924 147.600 ;
      RECT 0.096 148.272 105.924 148.368 ;
      RECT 0.096 149.040 105.924 149.136 ;
      RECT 0.096 149.808 105.924 149.904 ;
      RECT 0.096 150.576 105.924 150.672 ;
      RECT 0.096 151.344 105.924 151.440 ;
      RECT 0.096 152.112 105.924 152.208 ;
      RECT 0.096 152.880 105.924 152.976 ;
      RECT 0.096 153.648 105.924 153.744 ;
      RECT 0.096 154.416 105.924 154.512 ;
      RECT 0.096 155.184 105.924 155.280 ;
      RECT 0.096 155.952 105.924 156.048 ;
      RECT 0.096 156.720 105.924 156.816 ;
      RECT 0.096 157.488 105.924 157.584 ;
      RECT 0.096 158.256 105.924 158.352 ;
      RECT 0.096 159.024 105.924 159.120 ;
      RECT 0.096 159.792 105.924 159.888 ;
      RECT 0.096 160.560 105.924 160.656 ;
      RECT 0.096 161.328 105.924 161.424 ;
      RECT 0.096 162.096 105.924 162.192 ;
      RECT 0.096 162.864 105.924 162.960 ;
      RECT 0.096 163.632 105.924 163.728 ;
      RECT 0.096 164.400 105.924 164.496 ;
      RECT 0.096 165.168 105.924 165.264 ;
      RECT 0.096 165.936 105.924 166.032 ;
      RECT 0.096 166.704 105.924 166.800 ;
      RECT 0.096 167.472 105.924 167.568 ;
      RECT 0.096 168.240 105.924 168.336 ;
      RECT 0.096 169.008 105.924 169.104 ;
      RECT 0.096 169.776 105.924 169.872 ;
      RECT 0.096 170.544 105.924 170.640 ;
      RECT 0.096 171.312 105.924 171.408 ;
      RECT 0.096 172.080 105.924 172.176 ;
      RECT 0.096 172.848 105.924 172.944 ;
      RECT 0.096 173.616 105.924 173.712 ;
      RECT 0.096 174.384 105.924 174.480 ;
      RECT 0.096 175.152 105.924 175.248 ;
      RECT 0.096 175.920 105.924 176.016 ;
      RECT 0.096 176.688 105.924 176.784 ;
      RECT 0.096 177.456 105.924 177.552 ;
      RECT 0.096 178.224 105.924 178.320 ;
      RECT 0.096 178.992 105.924 179.088 ;
      RECT 0.096 179.760 105.924 179.856 ;
      RECT 0.096 180.528 105.924 180.624 ;
      RECT 0.096 181.296 105.924 181.392 ;
      RECT 0.096 182.064 105.924 182.160 ;
      RECT 0.096 182.832 105.924 182.928 ;
      RECT 0.096 183.600 105.924 183.696 ;
      RECT 0.096 184.368 105.924 184.464 ;
      RECT 0.096 185.136 105.924 185.232 ;
      RECT 0.096 185.904 105.924 186.000 ;
      RECT 0.096 186.672 105.924 186.768 ;
      RECT 0.096 187.440 105.924 187.536 ;
    END
  END VSS
  PIN VDD
    DIRECTION INOUT ;
    USE POWER ;
    PORT
      LAYER M4 ;
      RECT 0.096 0.432 105.924 0.528 ;
      RECT 0.096 1.200 105.924 1.296 ;
      RECT 0.096 1.968 105.924 2.064 ;
      RECT 0.096 2.736 105.924 2.832 ;
      RECT 0.096 3.504 105.924 3.600 ;
      RECT 0.096 4.272 105.924 4.368 ;
      RECT 0.096 5.040 105.924 5.136 ;
      RECT 0.096 5.808 105.924 5.904 ;
      RECT 0.096 6.576 105.924 6.672 ;
      RECT 0.096 7.344 105.924 7.440 ;
      RECT 0.096 8.112 105.924 8.208 ;
      RECT 0.096 8.880 105.924 8.976 ;
      RECT 0.096 9.648 105.924 9.744 ;
      RECT 0.096 10.416 105.924 10.512 ;
      RECT 0.096 11.184 105.924 11.280 ;
      RECT 0.096 11.952 105.924 12.048 ;
      RECT 0.096 12.720 105.924 12.816 ;
      RECT 0.096 13.488 105.924 13.584 ;
      RECT 0.096 14.256 105.924 14.352 ;
      RECT 0.096 15.024 105.924 15.120 ;
      RECT 0.096 15.792 105.924 15.888 ;
      RECT 0.096 16.560 105.924 16.656 ;
      RECT 0.096 17.328 105.924 17.424 ;
      RECT 0.096 18.096 105.924 18.192 ;
      RECT 0.096 18.864 105.924 18.960 ;
      RECT 0.096 19.632 105.924 19.728 ;
      RECT 0.096 20.400 105.924 20.496 ;
      RECT 0.096 21.168 105.924 21.264 ;
      RECT 0.096 21.936 105.924 22.032 ;
      RECT 0.096 22.704 105.924 22.800 ;
      RECT 0.096 23.472 105.924 23.568 ;
      RECT 0.096 24.240 105.924 24.336 ;
      RECT 0.096 25.008 105.924 25.104 ;
      RECT 0.096 25.776 105.924 25.872 ;
      RECT 0.096 26.544 105.924 26.640 ;
      RECT 0.096 27.312 105.924 27.408 ;
      RECT 0.096 28.080 105.924 28.176 ;
      RECT 0.096 28.848 105.924 28.944 ;
      RECT 0.096 29.616 105.924 29.712 ;
      RECT 0.096 30.384 105.924 30.480 ;
      RECT 0.096 31.152 105.924 31.248 ;
      RECT 0.096 31.920 105.924 32.016 ;
      RECT 0.096 32.688 105.924 32.784 ;
      RECT 0.096 33.456 105.924 33.552 ;
      RECT 0.096 34.224 105.924 34.320 ;
      RECT 0.096 34.992 105.924 35.088 ;
      RECT 0.096 35.760 105.924 35.856 ;
      RECT 0.096 36.528 105.924 36.624 ;
      RECT 0.096 37.296 105.924 37.392 ;
      RECT 0.096 38.064 105.924 38.160 ;
      RECT 0.096 38.832 105.924 38.928 ;
      RECT 0.096 39.600 105.924 39.696 ;
      RECT 0.096 40.368 105.924 40.464 ;
      RECT 0.096 41.136 105.924 41.232 ;
      RECT 0.096 41.904 105.924 42.000 ;
      RECT 0.096 42.672 105.924 42.768 ;
      RECT 0.096 43.440 105.924 43.536 ;
      RECT 0.096 44.208 105.924 44.304 ;
      RECT 0.096 44.976 105.924 45.072 ;
      RECT 0.096 45.744 105.924 45.840 ;
      RECT 0.096 46.512 105.924 46.608 ;
      RECT 0.096 47.280 105.924 47.376 ;
      RECT 0.096 48.048 105.924 48.144 ;
      RECT 0.096 48.816 105.924 48.912 ;
      RECT 0.096 49.584 105.924 49.680 ;
      RECT 0.096 50.352 105.924 50.448 ;
      RECT 0.096 51.120 105.924 51.216 ;
      RECT 0.096 51.888 105.924 51.984 ;
      RECT 0.096 52.656 105.924 52.752 ;
      RECT 0.096 53.424 105.924 53.520 ;
      RECT 0.096 54.192 105.924 54.288 ;
      RECT 0.096 54.960 105.924 55.056 ;
      RECT 0.096 55.728 105.924 55.824 ;
      RECT 0.096 56.496 105.924 56.592 ;
      RECT 0.096 57.264 105.924 57.360 ;
      RECT 0.096 58.032 105.924 58.128 ;
      RECT 0.096 58.800 105.924 58.896 ;
      RECT 0.096 59.568 105.924 59.664 ;
      RECT 0.096 60.336 105.924 60.432 ;
      RECT 0.096 61.104 105.924 61.200 ;
      RECT 0.096 61.872 105.924 61.968 ;
      RECT 0.096 62.640 105.924 62.736 ;
      RECT 0.096 63.408 105.924 63.504 ;
      RECT 0.096 64.176 105.924 64.272 ;
      RECT 0.096 64.944 105.924 65.040 ;
      RECT 0.096 65.712 105.924 65.808 ;
      RECT 0.096 66.480 105.924 66.576 ;
      RECT 0.096 67.248 105.924 67.344 ;
      RECT 0.096 68.016 105.924 68.112 ;
      RECT 0.096 68.784 105.924 68.880 ;
      RECT 0.096 69.552 105.924 69.648 ;
      RECT 0.096 70.320 105.924 70.416 ;
      RECT 0.096 71.088 105.924 71.184 ;
      RECT 0.096 71.856 105.924 71.952 ;
      RECT 0.096 72.624 105.924 72.720 ;
      RECT 0.096 73.392 105.924 73.488 ;
      RECT 0.096 74.160 105.924 74.256 ;
      RECT 0.096 74.928 105.924 75.024 ;
      RECT 0.096 75.696 105.924 75.792 ;
      RECT 0.096 76.464 105.924 76.560 ;
      RECT 0.096 77.232 105.924 77.328 ;
      RECT 0.096 78.000 105.924 78.096 ;
      RECT 0.096 78.768 105.924 78.864 ;
      RECT 0.096 79.536 105.924 79.632 ;
      RECT 0.096 80.304 105.924 80.400 ;
      RECT 0.096 81.072 105.924 81.168 ;
      RECT 0.096 81.840 105.924 81.936 ;
      RECT 0.096 82.608 105.924 82.704 ;
      RECT 0.096 83.376 105.924 83.472 ;
      RECT 0.096 84.144 105.924 84.240 ;
      RECT 0.096 84.912 105.924 85.008 ;
      RECT 0.096 85.680 105.924 85.776 ;
      RECT 0.096 86.448 105.924 86.544 ;
      RECT 0.096 87.216 105.924 87.312 ;
      RECT 0.096 87.984 105.924 88.080 ;
      RECT 0.096 88.752 105.924 88.848 ;
      RECT 0.096 89.520 105.924 89.616 ;
      RECT 0.096 90.288 105.924 90.384 ;
      RECT 0.096 91.056 105.924 91.152 ;
      RECT 0.096 91.824 105.924 91.920 ;
      RECT 0.096 92.592 105.924 92.688 ;
      RECT 0.096 93.360 105.924 93.456 ;
      RECT 0.096 94.128 105.924 94.224 ;
      RECT 0.096 94.896 105.924 94.992 ;
      RECT 0.096 95.664 105.924 95.760 ;
      RECT 0.096 96.432 105.924 96.528 ;
      RECT 0.096 97.200 105.924 97.296 ;
      RECT 0.096 97.968 105.924 98.064 ;
      RECT 0.096 98.736 105.924 98.832 ;
      RECT 0.096 99.504 105.924 99.600 ;
      RECT 0.096 100.272 105.924 100.368 ;
      RECT 0.096 101.040 105.924 101.136 ;
      RECT 0.096 101.808 105.924 101.904 ;
      RECT 0.096 102.576 105.924 102.672 ;
      RECT 0.096 103.344 105.924 103.440 ;
      RECT 0.096 104.112 105.924 104.208 ;
      RECT 0.096 104.880 105.924 104.976 ;
      RECT 0.096 105.648 105.924 105.744 ;
      RECT 0.096 106.416 105.924 106.512 ;
      RECT 0.096 107.184 105.924 107.280 ;
      RECT 0.096 107.952 105.924 108.048 ;
      RECT 0.096 108.720 105.924 108.816 ;
      RECT 0.096 109.488 105.924 109.584 ;
      RECT 0.096 110.256 105.924 110.352 ;
      RECT 0.096 111.024 105.924 111.120 ;
      RECT 0.096 111.792 105.924 111.888 ;
      RECT 0.096 112.560 105.924 112.656 ;
      RECT 0.096 113.328 105.924 113.424 ;
      RECT 0.096 114.096 105.924 114.192 ;
      RECT 0.096 114.864 105.924 114.960 ;
      RECT 0.096 115.632 105.924 115.728 ;
      RECT 0.096 116.400 105.924 116.496 ;
      RECT 0.096 117.168 105.924 117.264 ;
      RECT 0.096 117.936 105.924 118.032 ;
      RECT 0.096 118.704 105.924 118.800 ;
      RECT 0.096 119.472 105.924 119.568 ;
      RECT 0.096 120.240 105.924 120.336 ;
      RECT 0.096 121.008 105.924 121.104 ;
      RECT 0.096 121.776 105.924 121.872 ;
      RECT 0.096 122.544 105.924 122.640 ;
      RECT 0.096 123.312 105.924 123.408 ;
      RECT 0.096 124.080 105.924 124.176 ;
      RECT 0.096 124.848 105.924 124.944 ;
      RECT 0.096 125.616 105.924 125.712 ;
      RECT 0.096 126.384 105.924 126.480 ;
      RECT 0.096 127.152 105.924 127.248 ;
      RECT 0.096 127.920 105.924 128.016 ;
      RECT 0.096 128.688 105.924 128.784 ;
      RECT 0.096 129.456 105.924 129.552 ;
      RECT 0.096 130.224 105.924 130.320 ;
      RECT 0.096 130.992 105.924 131.088 ;
      RECT 0.096 131.760 105.924 131.856 ;
      RECT 0.096 132.528 105.924 132.624 ;
      RECT 0.096 133.296 105.924 133.392 ;
      RECT 0.096 134.064 105.924 134.160 ;
      RECT 0.096 134.832 105.924 134.928 ;
      RECT 0.096 135.600 105.924 135.696 ;
      RECT 0.096 136.368 105.924 136.464 ;
      RECT 0.096 137.136 105.924 137.232 ;
      RECT 0.096 137.904 105.924 138.000 ;
      RECT 0.096 138.672 105.924 138.768 ;
      RECT 0.096 139.440 105.924 139.536 ;
      RECT 0.096 140.208 105.924 140.304 ;
      RECT 0.096 140.976 105.924 141.072 ;
      RECT 0.096 141.744 105.924 141.840 ;
      RECT 0.096 142.512 105.924 142.608 ;
      RECT 0.096 143.280 105.924 143.376 ;
      RECT 0.096 144.048 105.924 144.144 ;
      RECT 0.096 144.816 105.924 144.912 ;
      RECT 0.096 145.584 105.924 145.680 ;
      RECT 0.096 146.352 105.924 146.448 ;
      RECT 0.096 147.120 105.924 147.216 ;
      RECT 0.096 147.888 105.924 147.984 ;
      RECT 0.096 148.656 105.924 148.752 ;
      RECT 0.096 149.424 105.924 149.520 ;
      RECT 0.096 150.192 105.924 150.288 ;
      RECT 0.096 150.960 105.924 151.056 ;
      RECT 0.096 151.728 105.924 151.824 ;
      RECT 0.096 152.496 105.924 152.592 ;
      RECT 0.096 153.264 105.924 153.360 ;
      RECT 0.096 154.032 105.924 154.128 ;
      RECT 0.096 154.800 105.924 154.896 ;
      RECT 0.096 155.568 105.924 155.664 ;
      RECT 0.096 156.336 105.924 156.432 ;
      RECT 0.096 157.104 105.924 157.200 ;
      RECT 0.096 157.872 105.924 157.968 ;
      RECT 0.096 158.640 105.924 158.736 ;
      RECT 0.096 159.408 105.924 159.504 ;
      RECT 0.096 160.176 105.924 160.272 ;
      RECT 0.096 160.944 105.924 161.040 ;
      RECT 0.096 161.712 105.924 161.808 ;
      RECT 0.096 162.480 105.924 162.576 ;
      RECT 0.096 163.248 105.924 163.344 ;
      RECT 0.096 164.016 105.924 164.112 ;
      RECT 0.096 164.784 105.924 164.880 ;
      RECT 0.096 165.552 105.924 165.648 ;
      RECT 0.096 166.320 105.924 166.416 ;
      RECT 0.096 167.088 105.924 167.184 ;
      RECT 0.096 167.856 105.924 167.952 ;
      RECT 0.096 168.624 105.924 168.720 ;
      RECT 0.096 169.392 105.924 169.488 ;
      RECT 0.096 170.160 105.924 170.256 ;
      RECT 0.096 170.928 105.924 171.024 ;
      RECT 0.096 171.696 105.924 171.792 ;
      RECT 0.096 172.464 105.924 172.560 ;
      RECT 0.096 173.232 105.924 173.328 ;
      RECT 0.096 174.000 105.924 174.096 ;
      RECT 0.096 174.768 105.924 174.864 ;
      RECT 0.096 175.536 105.924 175.632 ;
      RECT 0.096 176.304 105.924 176.400 ;
      RECT 0.096 177.072 105.924 177.168 ;
      RECT 0.096 177.840 105.924 177.936 ;
      RECT 0.096 178.608 105.924 178.704 ;
      RECT 0.096 179.376 105.924 179.472 ;
      RECT 0.096 180.144 105.924 180.240 ;
      RECT 0.096 180.912 105.924 181.008 ;
      RECT 0.096 181.680 105.924 181.776 ;
      RECT 0.096 182.448 105.924 182.544 ;
      RECT 0.096 183.216 105.924 183.312 ;
      RECT 0.096 183.984 105.924 184.080 ;
      RECT 0.096 184.752 105.924 184.848 ;
      RECT 0.096 185.520 105.924 185.616 ;
      RECT 0.096 186.288 105.924 186.384 ;
      RECT 0.096 187.056 105.924 187.152 ;
      RECT 0.096 187.824 105.924 187.920 ;
    END
  END VDD
  OBS
    LAYER M1 ;
    RECT 0 0 106.020 188.016 ;
    LAYER M2 ;
    RECT 0 0 106.020 188.016 ;
    LAYER M3 ;
    RECT 0 0 106.020 188.016 ;
    LAYER M4 ;
    RECT 0 0 106.020 188.016 ;
  END
END fakeram_w16_l32768

END LIBRARY
